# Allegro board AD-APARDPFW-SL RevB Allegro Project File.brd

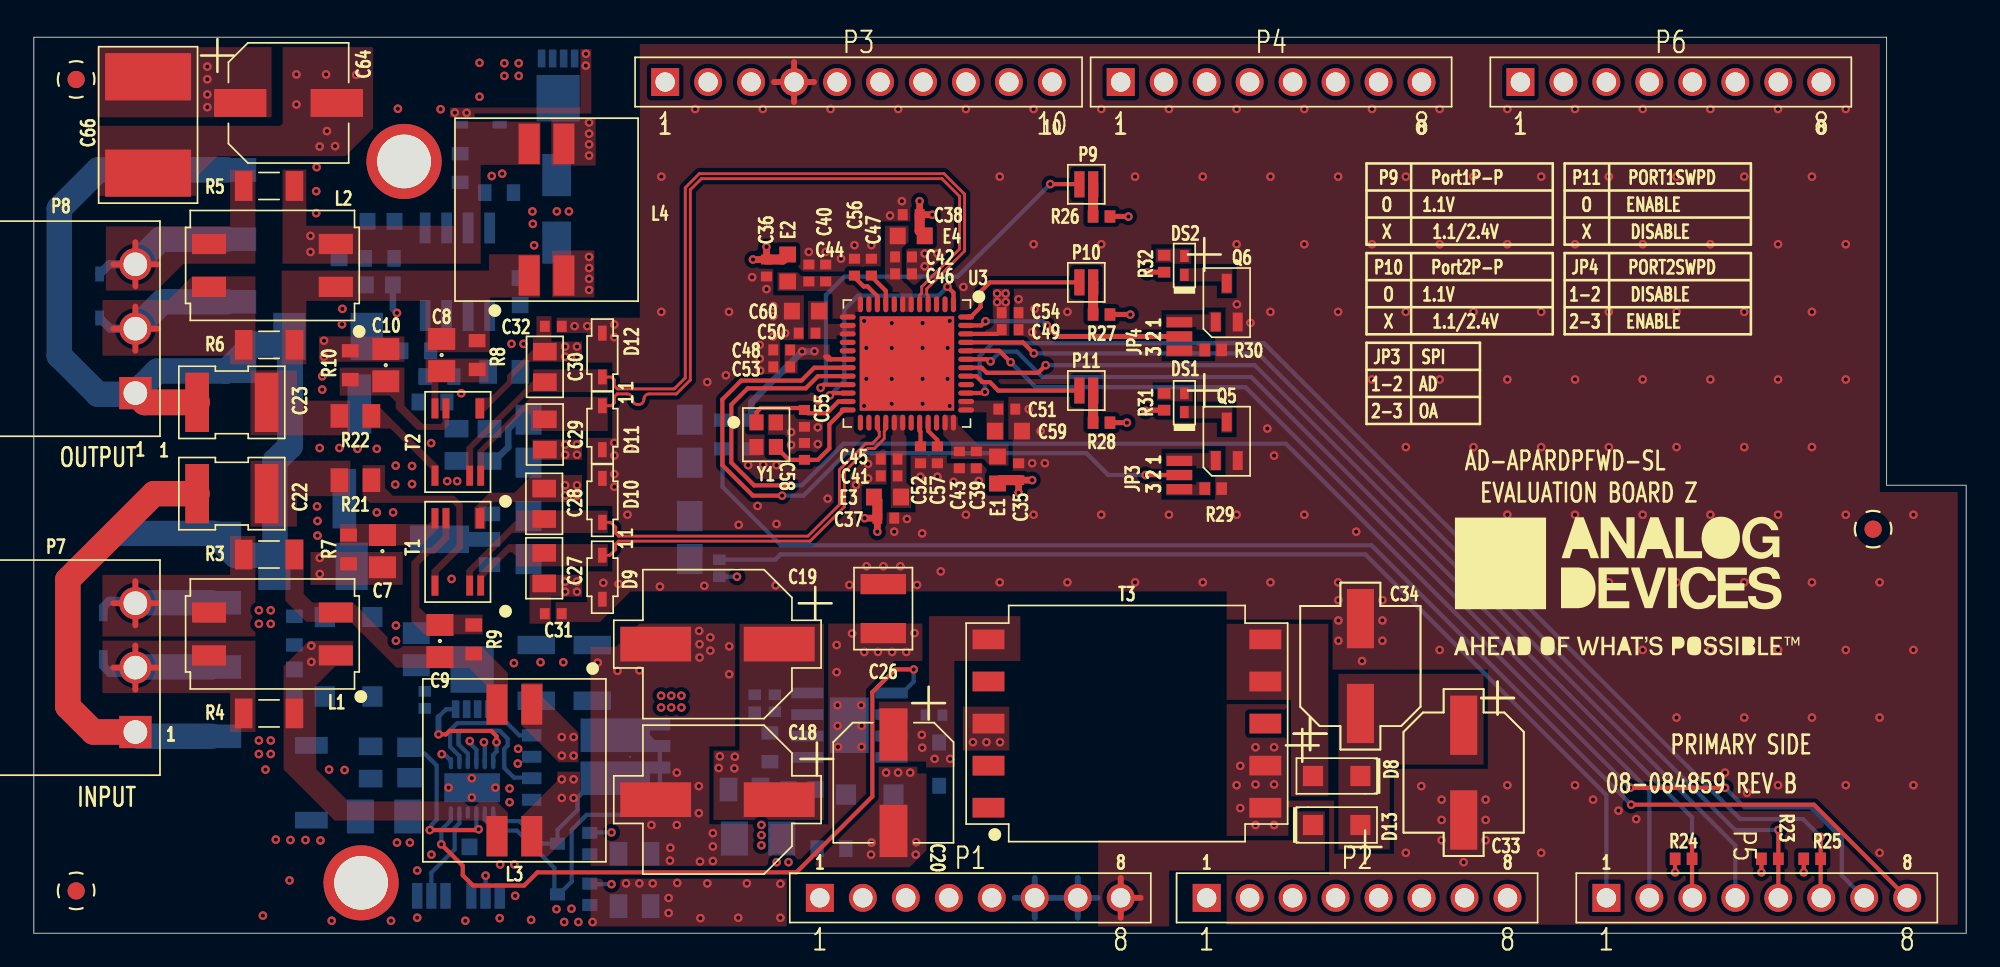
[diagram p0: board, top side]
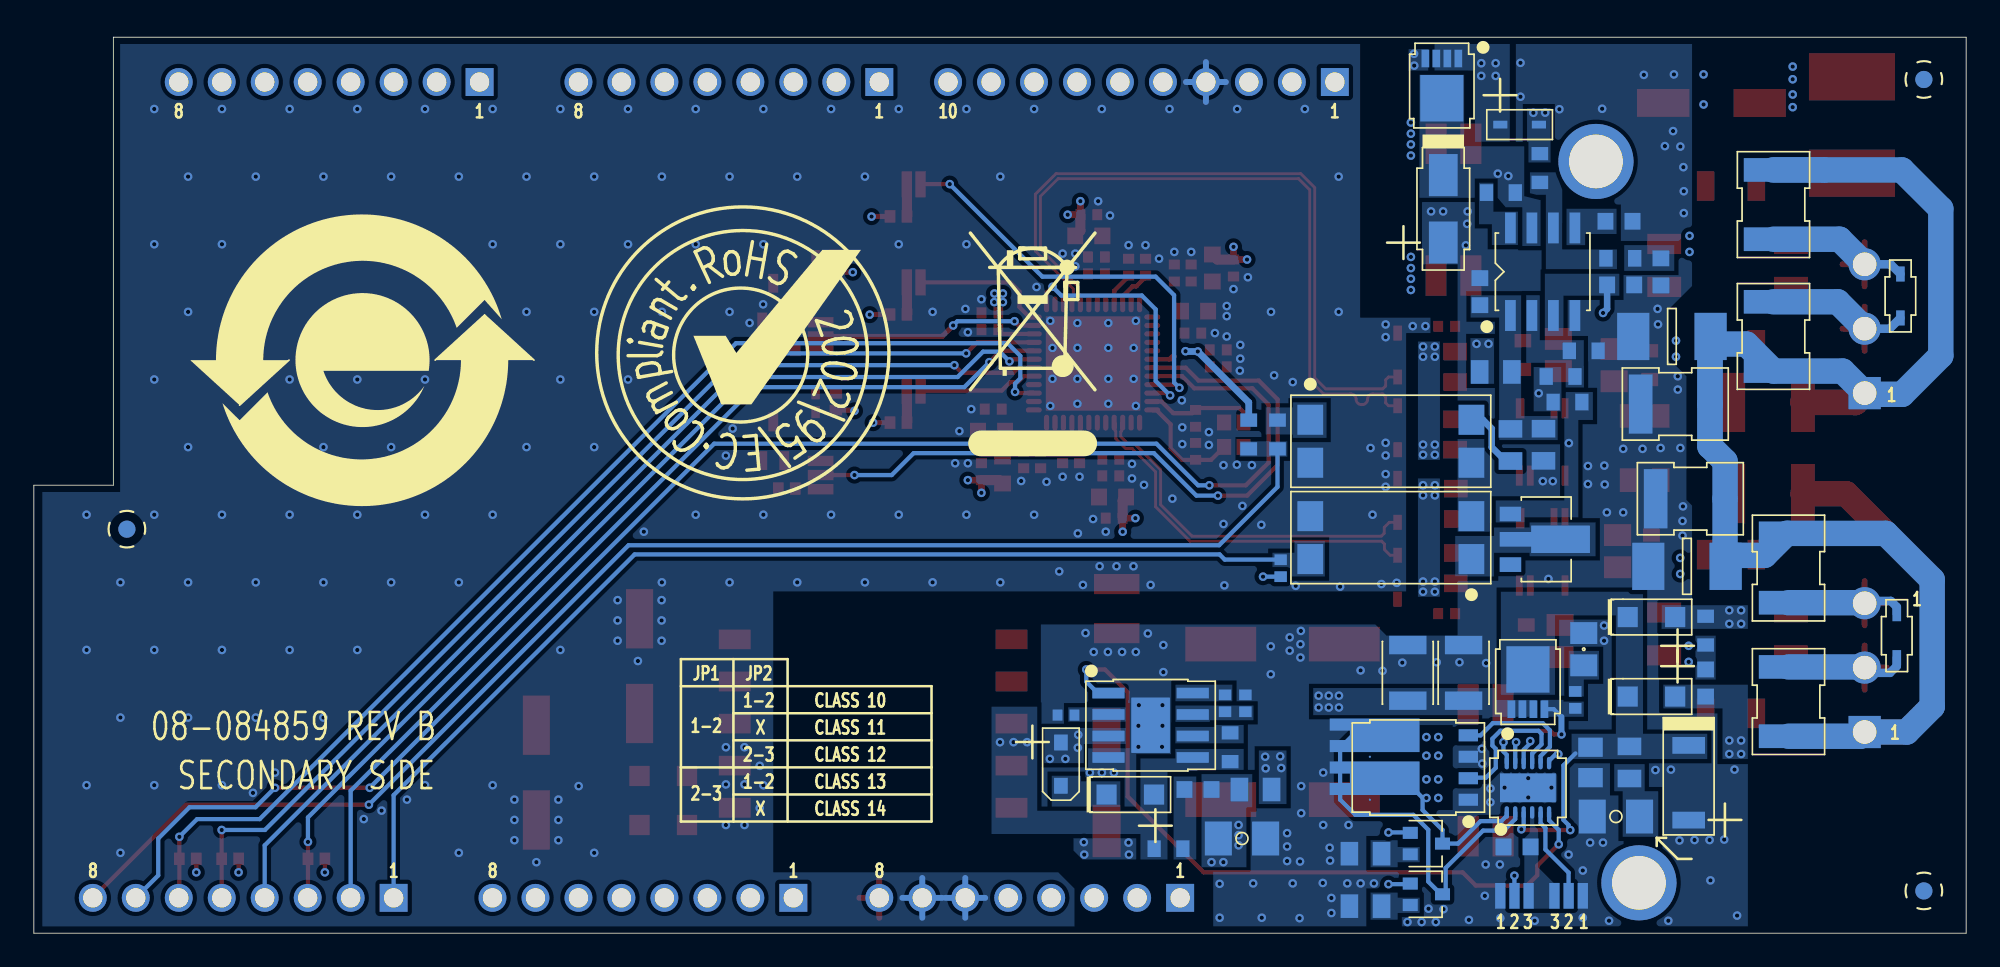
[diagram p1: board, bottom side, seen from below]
Outline 114.2 x 53 mm; copper layers: TOP, L2_PWR, L3_GND, BOTTOM. Coordinates in mm from the lower left corner of the outline.
Outline path: 0,53 109.5,53 109.5,26.5 114.2,26.5 114.2,0 0,0 0,53

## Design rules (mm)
constraint set DEFAULT: min track width 0.15
net group LTC_GATE: nets _N153 LTC_GATE
net group P2_TX: nets P2_TXN P2_TXP
net group 3V3_ARD: nets _N461 _N467 _N473 _N811 INT_N LT4256_UV_ISO SPI_CS SPI_MISO
net group LT4256_UV: nets _N154 _N710 _N711 _N712 _N767

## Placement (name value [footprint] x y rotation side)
C1  100pF  [C1812H71]  11.39 43.1 90 bottom
C2  100pF  [C1812H71]  10.5 21.6 90 bottom
C3  1000pF  [C1812H71]  16.3 25.7 0 bottom
C4  1000pF  [C1812H71]  17.19 31.3 0 bottom
C5  100pF  [C1812H71]  10.5 13.7 270 bottom
C6  100pF  [C1812H71]  11.39 35.3 270 bottom
C7  0.22uF  [C0805H60]  20.6 22.6 90 top
C8  0.22uF  [C0805H60]  24.1 34.2 270 top
C9  0.22uF  [C0805H60]  24 17.28 90 top
C10  0.22uF  [C0805H60]  20.8 33.6 270 top
C11  0.047UF  [C0603]  15.4 14.8 270 bottom
C12  150NF  [C1206H71]  20.7 6.9 0 bottom
C13  0.047uF  [C0805]  22.2 10.1 270 bottom
C14  0.022UF  [C0805H60]  22.6 16.8 270 bottom
C15  4.7uF  [C1210H87]  29.7 15.4 90 bottom
C16  4.7uF  [C1210H87]  33 15.4 90 bottom
C17  2.2uF  [C0603]  26.54 5.11 180 bottom
C18  33UF  [CPLSMSQ327H413]  40.4 7.9 180 top
C19  33UF  [CPLSMSQ327H413]  40.4 17.1 180 top
C20  22UF  [CPLSMSQ260H315]  50.8 8.9 270 top
C21  10UF  [C1206H71]  42.8 5.6 180 bottom
C22  100pF  [C1812H71]  11.7 26 0 top
C23  100pF  [C1812H71]  11.7 31.4 0 top
C24  1uF  [C0402]  53.2 12.9 0 bottom
C25  220pF  [C0603]  45.4 8.5 0 bottom
C26  4.7NF  [C1210H67]  50.2 19.2 90 top
C27  150pF  [C0805H30]  30.16 21.59 270 top
C28  150pF  [C0805H30]  30.16 25.4 270 top
C29  150pF  [C0805H30]  30.2 29.5 270 top
C30  150pF  [C0805H30]  30.2 33.5 270 top
C31  0.1uF  [C0402]  30.7 18.9 0 top
C32  0.1uF  [C0402]  30.7 35.9 0 top
C33  220UF  [CPLSMSQ260H303]  84.5 9.5 270 top
C34  220UF  [CPLSMSQ260H303]  78.4 15.8 90 top
C35  1uF  [C0402]  58.2 27.3 90 top
C36  1uF  [C0402]  43.3 39.35 270 top
C37  1uF  [C0402]  50.35 24.55 0 top
C38  1uF  [C0402]  51.85 42.5 180 top
C39  0.1uF  [C0402]  55.7 28 90 top
C40  0.1uF  [C0402]  45.8 39.05 90 top
C41  0.1uF  [C0402]  50.55 27.05 180 top
C42  0.1uF  [C0402]  51.4 40 0 top
C43  0.01uF  [C0402]  54.7 28 90 top
C44  0.01uF  [C0402]  46.8 39.05 90 top
C45  0.01uF  [C0402]  50.55 28.05 180 top
C46  0.01uF  [C0402]  51.4 39 0 top
C47  0.1uF  [C0402]  49.5 39.4 270 top
C48  0.01uF  [C0402]  44.2 34.5 180 top
C49  0.01uF  [C0402]  57.7 35.7 0 top
C50  0.1uF  [C0402]  45.7 35.5 180 top
C51  0.1uF  [C0402]  57.5 31 0 top
C52  0.1uF  [C0402]  52.4 28.3 270 top
C53  0.1uF  [C0402]  44.2 33.5 180 top
C54  0.1uF  [C0402]  57.7 36.7 0 top
C55  15pF  [C0402]  45.54 30.45 270 top
C56  1uF  [C0402]  48.5 39.4 90 top
C57  1uF  [C0402]  53.4 28.3 270 top
C58  15pF  [C0402]  45.54 28.5 90 top
C59  0.68UF  [C0603]  57.6 29.7 0 top
C60  0.68UF  [C0603]  45.6 36.8 180 top
C61  0.1UF  [C0603]  28.74 37.95 90 bottom
C62  1NF  [C0603]  18.04 39.12 270 bottom
C63  0.033uF  [C0603]  20.52 42.11 180 bottom
C64  22UF  [CPLSMSQ260H315]  15.05 49.11 0 top
C65  0.1UF  [C0603]  20.42 38.35 180 bottom
C66  22UF  [C2220H122]  6.75 47.81 270 top
D1  D55V0M1B2WSQ-7  [SOD323_B]  4.1 17.6 270 bottom
D2  D55V0M1B2WSQ-7  [SOD323_B]  3.89 37.69 270 bottom
D3  PMEG10020AELRX  [SOD123F]  18.6 18.7 180 bottom
D4  PMEG10020AELRX  [SOD123F]  18.6 14 180 bottom
D5  PTVS58VP1UTP  [SOD128]  16.4 8.9 270 bottom
D6  BZX384-B51  [SOD323-2]  53.5 10 90 bottom
D7  PMEG10020AELRX  [SOD123F]  49.4 8.2 180 bottom
D8  PMEG10020AELRX  [SOD123F]  77 9.3 180 top
D9  SP4020-01FTG  [SOD323_B]  33.6 21.06 270 top
D10  SP4020-01FTG  [SOD323_B]  33.6 25.6 90 top
D11  SP4020-01FTG  [SOD323_B]  33.6 29.9 270 top
D12  SP4020-01FTG  [SOD323_B]  33.6 34.2 90 top
D13  PMEG10020AELRX  [SOD123F]  77 6.4 0 top
D14  SMAT70A-13-F  [SMA-2]  30.9 42.85 270 bottom
D15  MM3Z11VB  [SOD323F]  26.39 47.83 0 bottom
DS1  APHHS1005CGCK  [LED0402_A]  68 31.38 90 top
DS2  APHHS1005CGCK  [LED0402_A]  68 39.5 90 top
E1  1KOHM AT 100MEGHZ  [L0603]  56.95 27.4 270 top
E2  1KOHM AT 100MEGHZ  [L0603]  44.55 39.35 270 top
E3  1KOHM AT 100MEGHZ  [L0603]  50.45 25.8 0 top
E4  1KOHM AT 100MEGHZ  [L0603]  51.85 41.25 180 top
JP1  3PIN_SOLDER_JUMPER  [JPRSLD03]  23.5 2.21 0 bottom
JP2  3PIN_SOLDER_JUMPER  [JPRSLD03]  26.7 2.21 180 bottom
JP3  3PIN_SOLDER_JUMPER  [JPRSLD03]  67.7 27.1 270 top
JP4  3PIN_SOLDER_JUMPER  [JPRSLD03]  67.7 35.3 270 top
L1  470UH  [LSML236W362H209]  14.1 17.7 90 top
L2  470UH  [LSML236W362H209]  14.1 39.5 90 top
L3  68UH  [LSMSQ406H197]  28.4 9.63 270 top
L4  68UH  [LSMSQ406H197]  30.3 42.8 90 top
NOREF  -  []  -272.1 -221.5 0 top
NOREF#2  -  [unnamed#2]  19.34 2.98 0 top
NOREF#3  -  []  109.5 53 180 top
NOREF#4  -  []  139.25 62 0 top
NOREF#5  -  []  0 0 0 top
NOREF#6  -  []  114.2 0 90 top
NOREF#7  -  [unnamed#2]  2.5 50.5 0 top
NOREF#8  -  []  -49.41 -241.98 0 top
NOREF#9  -  []  0 53 0 top
NOREF#10  -  []  -36 -105 0 top
NOREF#11  -  []  -36 -105 0 top
NOREF#12  -  [unnamed#2]  21.88 45.65 0 top
NOREF#13  -  []  -24.12 206.26 0 top
NOREF#14  -  []  93.58 20.51 0 top
NOREF#15  -  []  0 53 270 top
NOREF#16  -  [unnamed#2]  2.5 2.5 0 top
NOREF#17  -  []  7.6 -60.8 0 top
NOREF#18  -  []  55.75 67.75 0 top
NOREF#19  -  [unnamed#2]  108.7 23.9 0 top
NOREF#20  -  []  114.2 0 90 top
NOREF#21  -  [unnamed#2]  108.7 23.9 180 bottom
NOREF#22  -  []  94.8 33.9 180 bottom
NOREF#23  -  []  72.3 34.2 180 bottom
NOREF#24  -  [unnamed#2]  2.5 50.5 180 bottom
NOREF#25  -  [unnamed#2]  2.5 2.5 180 bottom
NOREF#26  -  []  45.9 45.1 180 bottom
P1  ESQ-108-24-T-S  [CNTHFHDR1X8L820W95H545]  46.45 2.09 0 top
P2  ESQ-108-24-T-S  [CNTHFHDR1X8L820W95H545]  69.31 2.09 0 top
P3  ESQ-110-24-T-S  [CNTHFHDR1X10L1020W95H545]  37.31 50.35 0 top
P4  ESQ-108-24-T-S  [CNTHFHDR1X8L820W95H545]  64.23 50.35 0 top
P5  ESQ-108-24-T-S  [CNTHFHDR1X8L820W95H545]  92.94 2.09 0 top
P6  ESQ-108-24-T-S  [CNTHFHDR1X8L820W95H545]  87.86 50.35 0 top
P7  TBP02R1-381-03BE  [CNCUITBP02R1-381-03BE]  6 11.9 90 top
P8  TBP02R1-381-03BE  [CNCUITBP02R1-381-03BE]  6 31.95 90 top
P9  -  [JPSLD02]  62.2 44.3 0 top
P10  -  [JPSLD02]  62.2 38.5 0 top
P11  -  [JPSLD02]  62.2 32.1 0 top
Q1  BSS123WQ-7-F  [SOT323]  31.9 5.3 270 bottom
Q2  BSS123WQ-7-F  [SOT323]  31.9 2.3 270 bottom
Q3  BUK9K29-100E,115  [SOT1205]  32.7 9.8 90 bottom
Q4  PSMN075-100MSEX  [SOT1210]  25.9 14.9 180 bottom
Q5  BSS138PW,115  [SC-70-3]  70.5 29.1 0 top
Q6  BSS138PW,115  [SC-70-3]  70.5 37.3 0 top
Q7  PSMN075-100MSEX  [SOT1210]  30.99 50.09 0 bottom
Q8  FOD817AS  [SMD4]  34 23.4 90 bottom
Q9  FOD817AS  [SMD4]  34 29.1 270 bottom
R1  4.7MEG  [R2010]  16.5 21.7 0 bottom
R2  4.7MEG  [R2010]  17.39 35.3 0 bottom
R3  10K  [R1206]  13.9 22.4 0 top
R4  10K  [R1206]  13.9 13 0 top
R5  10K  [R1206]  13.9 44.2 0 top
R6  10K  [R1206]  13.9 34.8 0 top
R7  1MEG  [R0603]  18.6 22.7 90 top
R8  1MEG  [R0603]  26.2 34.2 270 top
R9  1MEG  [R0603]  26 17.38 90 top
R10  1MEG  [R0603]  18.7 33.6 270 top
R11  3.3  [R0805]  35.5 4.7 0 bottom
R12  100  [R0603]  15.4 17.9 270 bottom
R13  3.3  [R0805]  35.5 1.6 0 bottom
R14  40.2  [R0805]  19.9 10.1 270 bottom
R15  10K  [R0402]  23.1 13.8 270 bottom
R16  3.3  [R0805]  42 8.5 180 bottom
R17  10K  [R0402]  42.6 13.6 90 bottom
R18  100K  [R0402]  43.8 13.6 90 bottom
R19  261K  [R0603]  43.5 11 270 bottom
R20  100  [R0603]  47.14 5 0 bottom
R21  100  [R0805]  19 26.8 0 top
R22  100  [R0805]  19 30.6 0 top
R23  100K  [R0402]  102.6 4.4 0 top
R24  100K  [R0402]  97.5 4.4 0 top
R25  1.5K  [R0402]  105.1 4.4 0 top
R26  4.7K  [R0402]  63.1 42.4 0 top
R27  4.7K  [R0402]  63.1 36.6 0 top
R28  4.7K  [R0402]  63.1 30.2 0 top
R29  4.7K  [R0402]  69.7 26.3 0 top
R30  4.7K  [R0402]  69.7 34.5 0 top
R31  1K  [R0402]  66.8 31.44 90 top
R32  1K  [R0402]  66.8 39.6 90 top
R33  0.075  [R0603]  27.5 43.81 0 bottom
R34  100  [R0603]  20.44 39.92 180 bottom
R35  10  [R0603]  25.2 45.26 270 bottom
R36  100K  [R0603]  23.97 32.93 180 bottom
R37  24.3K  [R0603]  22.6 34.45 0 bottom
R39  34K  [R0603]  23.56 31.42 180 bottom
R40  10K  [R0402]  40.51 21.59 90 bottom
R41  100  [R0603]  40.7 29.5 90 bottom
R42  330K  [R0805]  27.8 33.2 180 bottom
R43  20K  [R0805]  26.93 28.88 270 bottom
R44  10K  [R0603]  42.4 29.5 270 bottom
R45  330K  [R0805]  24.98 28.89 270 bottom
T1  74930000  [TSML185W127H114_A]  25.06 22.56 90 top
T2  74930000  [TSML185W127H114_A]  25.06 29.06 90 top
T3  750315126  [TSMSQ530H505]  64.6 12.4 90 top
U1  LTC9111RDE#PBF  [DFN12_4X3_PAD3_3X1_7-05-08-1695]  25.9 8.6 180 bottom
U2  LT8304IS8E#PBF  [SO8NB_PAD3_27X2_28-05-08-1857]  48.2 12.3 270 bottom
U3  ADIN2111CCPZ  [QFN48_7X7_PAD5_6X5_6]  51.6 33.7 180 top
U4  LT4256-2IS8#TRPBF  [SO8NB-5]  25.03 39.13 180 bottom
U5  CL2N8-G  [SOT-89-2]  24.9 23.3 270 bottom
Y1  25MEGHZ  [YSML79W63H20]  43.28 29.49 270 top

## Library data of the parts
C1 C2 C5 C6 C22 C23 = CAP: Tolerance: 5; User Part Number: UPN; alternate symbols: (C1812H71); tolerance: 5
C3 C4 = CAP: Tolerance: 10; User Part Number: UPN; alternate symbols: (C1812H71); tolerance: 10
C7-C10 C14 = CAP: Tolerance: 5; User Part Number: UPN; alternate symbols: (C0805H60); tolerance: 5
C11 C17 C59-C62 C65 = CAP: User Part Number: UPN; Tolerance: 10; alternate symbols: (C0603); tolerance: 10
C12 C21 = CAP: Tolerance: 10; User Part Number: UPN; alternate symbols: (C1206H71); tolerance: 10
C13 = CAP: User Part Number: UPN; Tolerance: 10; alternate symbols: (C0805); tolerance: 10
C15 C16 = CAP: Tolerance: 10; User Part Number: UPN; alternate symbols: (C1210H87); tolerance: 10
C18 C19 = CAPP: User Part Number: UPN; Tolerance: 20; alternate symbols: (CPLSMSQ327H413); tolerance: 20
C20 C64 = CAPP: Tolerance: 20; User Part Number: UPN; alternate symbols: (CPLSMSQ260H315); tolerance: 20
C24 C31 C32 C35-C54 C56 C57 = CAP: User Part Number: UPN; Tolerance: 10; alternate symbols: (C0402); tolerance: 10
C25 C63 = CAP: User Part Number: UPN; Tolerance: 5; alternate symbols: (C0603); tolerance: 5
C26 = CAP: Tolerance: 10; User Part Number: UPN; alternate symbols: (C1210H67); tolerance: 10
C27-C30 = CAP: Tolerance: 1; User Part Number: UPN; alternate symbols: (C0805H30); tolerance: 1
C33 C34 = CAPP: User Part Number: UPN; Tolerance: 20; alternate symbols: (CPLSMSQ260H303); tolerance: 20
C55 C58 = CAP: User Part Number: UPN; Tolerance: 1; alternate symbols: (C0402); tolerance: 1
C66 = CAP: Tolerance: 20; User Part Number: UPN; alternate symbols: (C2220H122); tolerance: 20
D1 D2 = DIOZNR_V2: Tolerance: N/A; User Part Number: UPN; alternate symbols: (SOD323_B); tolerance: N/A
D3 D4 D7 D8 D13 = DIOSCHOTTKY: Tolerance: N/A; User Part Number: UPN; alternate symbols: (SOD123F); tolerance: N/A
D5 = DIOZNR: User Part Number: UPN; Tolerance: N/A; alternate symbols: (SOD128); tolerance: N/A
D6 = DIOZNR: Tolerance: 2; User Part Number: UPN; alternate symbols: (SOD323-2); tolerance: 2
D9-D12 = DIOZNR_V4: Tolerance: N/A; User Part Number: UPN; alternate symbols: (SOD323_B); tolerance: N/A
D14 = DIOTVS: User Part Number: UPN; Tolerance: N/A; alternate symbols: (SMA-2); tolerance: N/A
D15 = DIOZNR: Tolerance: 2; User Part Number: UPN; alternate symbols: (SOD323F); tolerance: 2
DS1 DS2 = DIOLED: User Part Number: UPN; Tolerance: N/A; alternate symbols: (LED0402_A); tolerance: N/A
E1-E4 = FERRITE: User Part Number: UPN; Tolerance: 25; alternate symbols: (L0603); tolerance: 25
JP1-JP4 = NC3P_JMPR: Tolerance: N/A; User Part Number: UPN; alternate symbols: (JPRSLD03); tolerance: N/A
L1 L2 = CHOKE4P_V5: User Part Number: UPN; Tolerance: 50; alternate symbols: (LSML236W362H209); tolerance: 50
L3 L4 = IND_4P_V4: User Part Number: UPN; Tolerance: 20; alternate symbols: (LSMSQ406H197); tolerance: 20
P1 P2 P4-P6 = CN8P_A: User Part Number: UPN; Tolerance: N/A; alternate symbols: (CNTHFHDR1X8L820W95H545); tolerance: N/A
P3 = CN10P: User Part Number: UPN; Tolerance: N/A; alternate symbols: (CNTHFHDR1X10L1020W95H545); tolerance: N/A
P7 P8 = CN3P: User Part Number: UPN; Tolerance: N/A; alternate symbols: (CNCUITBP02R1-381-03BE); tolerance: N/A
P9-P11 = NC2P: User Part Number: UPN; Tolerance: N/A; alternate symbols: (JPSLD02); tolerance: N/A
Q1 Q2 = TRANNMOSFET_V8: User Part Number: UPN; Tolerance: N/A; alternate symbols: (SOT323); tolerance: N/A
Q3 = TRANNMOSFET_DUAL: Tolerance: N/A; User Part Number: UPN; alternate symbols: (SOT1205); tolerance: N/A
Q4 Q7 = TRANNMOSFET_V15: Tolerance: N/A; User Part Number: UPN; alternate symbols: (SOT1210); tolerance: N/A
Q5 Q6 = TRANNMOSFET_V8: Tolerance: N/A; User Part Number: UPN; alternate symbols: (SC-70-3); tolerance: N/A
Q8 Q9 = TRANOPTO: Tolerance: N/A; User Part Number: UPN; alternate symbols: (SMD4); tolerance: N/A
R1 R2 = RES: Tolerance: 5; User Part Number: UPN; alternate symbols: (R2010); tolerance: 5
R3-R6 = RES: User Part Number: UPN; Tolerance: 1; alternate symbols: (R1206); tolerance: 1
R7-R10 R12 R19 R20 R33 R34 R36 R37 R39 R41 R44 = RES: User Part Number: UPN; Tolerance: 1; alternate symbols: (R0603); tolerance: 1
R11 R13 R16 R42 R45 = RES: User Part Number: UPN; Tolerance: 5; alternate symbols: (R0805); tolerance: 5
R14 R21 R22 R43 = RES: User Part Number: UPN; Tolerance: 1; alternate symbols: (R0805); tolerance: 1
R15 R17 R23-R25 R31 R32 R40 = RES: User Part Number: UPN; Tolerance: 1; alternate symbols: (R0402); tolerance: 1
R18 R26-R30 = RES: User Part Number: UPN; Tolerance: 5; alternate symbols: (R0402); tolerance: 5
R35 = RES: User Part Number: UPN; Tolerance: 0.5; alternate symbols: (R0603); tolerance: 0.5
T1 T2 = XFMR7P_V2: User Part Number: UPN; Tolerance: N/A; alternate symbols: (TSML185W127H114_A); tolerance: N/A
T3 = XFMR10P_V16: User Part Number: UPN; Tolerance: N/A; alternate symbols: (TSMSQ530H505); tolerance: N/A
U1 = ADLTC9111_V2: User Part Number: UPN; Tolerance: N/A; alternate symbols: (DFN12_4X3_PAD3_3X1_7-05-08-1695); tolerance: N/A
U2 = ADLT8304: Tolerance: N/A; User Part Number: UPN; alternate symbols: (SO8NB_PAD3_27X2_28-05-08-1857); tolerance: N/A
U3 = ADIN2111: User Part Number: UPN; Tolerance: N/A; alternate symbols: (QFN48_7X7_PAD5_6X5_6); tolerance: N/A
U4 = ADLT4256_X: Tolerance: N/A; User Part Number: UPN; alternate symbols: (SO8NB-5); tolerance: N/A
U5 = ICCL2: User Part Number: UPN; Tolerance: N/A; alternate symbols: (SOT-89-2); tolerance: N/A
Y1 = XTAL4PIN_V3: Tolerance: 10PPM; User Part Number: UPN; alternate symbols: (YSML79W63H20); tolerance: 10PPM

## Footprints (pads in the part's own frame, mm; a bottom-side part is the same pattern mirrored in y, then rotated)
C0402
  rect 0.584x0.66 smd: 1(-0.5,0) 2(0.5,0)
C0603
  rect 0.94x0.991 smd: 1(-0.8,0) 2(0.8,0)
C0805
  rect 1.143x1.448 smd: 1(-0.9,0) 2(0.9,0)
C0805H30
  rect 1.041x1.397 smd: 1(-0.9,0) 2(0.9,0)
C0805H60
  rect 1.295x1.6 smd: 1(-0.952,0) 2(0.952,0)
C1206H71
  rect 1.6x2.007 smd: 1(-1.397,0) 2(1.397,0)
C1210H67
  rect 1.194x2.692 smd: 1(-1.448,0) 2(1.448,0)
C1210H87
  rect 1.092x2.21 smd: 1(-1.646,0) 2(1.646,0)
C1812H71
  rect 1.397x3.505 smd: 1(-2.05,0) 2(2.05,0)
C2220H122
  rect 2.794x5.08 smd: 1(-2.85,0) 2(2.85,0)
CNCUITBP02R1-381-03BE
  rect 1.905x1.905 hole 1.397: 1(0,0)
  round 1.905 hole 1.397: 2(3.81,0) 3(7.62,0)
CNTHFHDR1X8L820W95H545
  rect 1.651x1.651 hole 1.143: 1(0,0)
  round 1.651 hole 1.143: 2(2.54,0) 3(5.08,0) 4(7.62,0) 5(10.16,0) 6(12.7,0) 7(15.24,0) 8(17.78,0)
CNTHFHDR1X10L1020W95H545
  rect 1.651x1.651 hole 1.143: 1(0,0)
  round 1.651 hole 1.143: 2(2.54,0) 3(5.08,0) 4(7.62,0) 5(10.16,0) 6(12.7,0) 7(15.24,0) 8(17.78,0) 9(20.32,0) 10(22.86,0)
CPLSMSQ260H303
  rect 3.505x1.6 smd: N(2.803,0) P(-2.803,0)
CPLSMSQ260H315
  rect 3.099x1.651 smd: N(2.85,0) P(-2.85,0)
CPLSMSQ327H413
  rect 4.191x2.057 smd: N(3.65,0) P(-3.65,0)
DFN12_4X3_PAD3_3X1_7-05-08-1695
  oval 0.254x0.737 smd: 1(-1.25,-1.46) 2(-0.75,-1.46) 3(-0.25,-1.46) 4(0.25,-1.46) 5(0.75,-1.46) 6(1.25,-1.46) 7(1.25,1.46) 8(0.75,1.46) 9(0.25,1.46) 10(-0.25,1.46) 11(-0.75,1.46) 12(-1.25,1.46)
  rect 3.302x1.702 smd: 13(0,0)
JPRSLD03
  rect 0.61x1.524 smd: 1(-0.838,0) 2(0,0) 3(0.838,0)
JPSLD02
  rect 0.61x1.549 smd: 1(-0.406,0) 2(0.406,0)
L0603
  rect 0.94x0.991 smd: 1(-0.8,0) 2(0.8,0)
LED0402_A
  rect 0.711x0.508 smd: A(0.556,0) C(-0.556,0)
LSML236W362H209
  rect 1.194x2.007 smd: 1(-1.27,-3.747) 2(1.27,-3.747) 3(1.27,3.747) 4(-1.27,3.747)
LSMSQ406H197
  rect 2.388x1.245 smd: 1(-3.899,1.029) 2(-3.899,-1.029) 3(3.899,-1.029) 4(3.899,1.029)
QFN48_7X7_PAD5_6X5_6
  oval 0.305x0.94 smd: 1(-2.75,-3.5) 2(-2.25,-3.5) 3(-1.75,-3.5) 4(-1.25,-3.5) 5(-0.75,-3.5) 6(-0.25,-3.5) 7(0.25,-3.5) 8(0.75,-3.5) 9(1.25,-3.5) 10(1.75,-3.5) 11(2.25,-3.5) 12(2.75,-3.5) 25(2.75,3.5) 26(2.25,3.5) 27(1.75,3.5) 28(1.25,3.5) 29(0.75,3.5) 30(0.25,3.5) 31(-0.25,3.5) 32(-0.75,3.5) 33(-1.25,3.5) 34(-1.75,3.5) 35(-2.25,3.5) 36(-2.75,3.5)
  oval 0.94x0.305 smd: 13(3.5,-2.75) 14(3.5,-2.25) 15(3.5,-1.75) 16(3.5,-1.25) 17(3.5,-0.75) 18(3.5,-0.25) 19(3.5,0.25) 20(3.5,0.75) 21(3.5,1.25) 22(3.5,1.75) 23(3.5,2.25) 24(3.5,2.75) 37(-3.5,2.75) 38(-3.5,2.25) 39(-3.5,1.75) 40(-3.5,1.25) 41(-3.5,0.75) 42(-3.5,0.25) 43(-3.5,-0.25) 44(-3.5,-0.75) 45(-3.5,-1.25) 46(-3.5,-1.75) 47(-3.5,-2.25) 48(-3.5,-2.75)
  rect 5.588x5.588 smd: PAD(0,0)
R0402
  rect 0.635x0.737 smd: 1(-0.5,0) 2(0.5,0)
R0603
  rect 0.787x0.991 smd: 1(-0.85,0) 2(0.85,0)
R0805
  rect 1.041x1.397 smd: 1(-0.95,0) 2(0.95,0)
R1206
  rect 1.041x1.753 smd: 1(-1.5,0) 2(1.5,0)
R2010
  rect 1.905x2.794 smd: 1(-2.286,0) 2(2.286,0)
SC-70-3
  rect 0.584x1.118 smd: 1(-0.65,-1.144) 2(0.65,-1.144) 3(0,1.144)
SMA-2
  rect 2.489x1.702 smd: A(1.995,0) C(-1.995,0)
SMD4
  rect 1.778x1.524 smd: 1(-1.27,-4.763) 2(1.27,-4.763) 3(1.27,4.763) 4(-1.27,4.763)
SO8NB-5
  rect 0.635x1.829 smd: 1(-1.905,-2.591) 2(-0.635,-2.591) 3(0.635,-2.591) 4(1.905,-2.591) 5(1.905,2.591) 6(0.635,2.591) 7(-0.635,2.591) 8(-1.905,2.591)
SO8NB_PAD3_27X2_28-05-08-1857
  rect 0.635x1.905 smd: 1(-1.905,-2.49) 2(-0.635,-2.49) 3(0.635,-2.49) 4(1.905,-2.49) 5(1.905,2.49) 6(0.635,2.49) 7(-0.635,2.49) 8(-1.905,2.49)
  rect 3.277x2.286 smd: 9(0,0)
SOD123F
  rect 1.194x1.194 smd: A(1.403,0) C(-1.403,0)
SOD128
  rect 0.991x1.93 smd: A(2.21,0) C(-2.21,0)
SOD323-2
  rect 0.94x0.813 smd: A(1.28,0) C(-1.28,0)
SOD323_B
  rect 0.889x0.508 smd: 1(-1.3,0) 2(1.3,0)
SOD323F
  rect 0.838x0.457 smd: A(1.14,0) C(-1.14,0)
SOT323
  rect 0.711x0.889 smd: 1(-0.635,-0.952) 2(0.635,-0.952) 3(0,0.952)
SOT1205
  rect 0.711x1.143 smd: 1(-1.905,-3.278) 2(-0.635,-3.278) 3(0.635,-3.278) 4(1.905,-3.278)
  custom 0.495x0.495 smd: 5(1.905,2.26) 7(-0.635,2.26)
  round 0.127 smd: 6(0.635,2.54) 8(-1.905,2.54)
SOT1210
  rect 0.457x1.041 smd: 1(-0.975,-1.65) 2(-0.325,-1.65) 3(0.325,-1.65) 4(0.975,-1.65)
  round 0.127 smd: 5(0.975,1.65) 6(0.325,1.65) 7(-0.325,1.65) 8(-0.975,1.65)
SOT-89-2
  rect 0.864x1.27 smd: 1(-1.499,-2.032) 3(1.499,-2.032)
  custom 0.406x0.406 smd: 2(0,0)
TSML185W127H114_A
  rect 1.194x0.406 smd: 1(-1.99,-1.35) 2(-1.99,-0.7) 3(-1.99,1.35) 6(1.99,0.7) 7(1.99,1.35)
  round 0.127 smd: 4(-1.69,1.35)
  rect 1.194x0.508 smd: 5(1.99,-1.305)
TSMSQ530H505
  rect 1.168x1.88 smd: 1(-4.978,8.179) 2(-2.489,8.179) 3(0,8.179) 4(2.489,8.179) 5(4.978,8.179) 6(4.978,-8.179) 7(2.489,-8.179) 8(0,-8.179) 9(-2.489,-8.179) 10(-4.978,-8.179)
unnamed#2
  round 4.445 hole 3.175 unplated: (0,0)
YSML79W63H20
  rect 0.94x0.838 smd: 1(-0.725,-0.575) 2(0.725,-0.575) 3(0.725,0.575) 4(-0.725,0.575)

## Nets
3V3_ARD: C35.1 C36.1 C37.1 C38.1 C48.1 C49.1 C53.1 C54.1 E1.2(N2) E2.1 E3.1 E4.1 P1.4 R23.1 R24.1 R25.1 R26.2(N2) R27.2(N2) R28.2(N2) R31.1 R32.1 R40.1 R44.1 U3.18 U3.46
12V_ISO: D13.C P1.8(N8)
DGND: C26.2(N2) C31.2(N2) C32.2(N2) C33.N(N2) C34.N(N2) C35.2(N2) C36.2(N2) C37.2(N2) C38.2(N2) C39.1 C40.2(N2) C41.2(N2) C42.2(N2) C43.1 C44.2(N2) C45.2(N2) C46.2(N2) C47.1 C48.2(N2) C49.2(N2) C50.2(N2) C51.2(N2) C52.2(N2) C53.2(N2) C54.2(N2) C55.2(N2) C56.2(N2) C57.2(N2) C58.2(N2) C59.2(N2) C60.2(N2) D9.2(N2) D10.2(N2) D11.2(N2) D12.2(N2) P1.6 P1.7 P3.4 Q5.2(S) Q6.2(S) Q8.3(E) Q9.2 R29.2(N2) R30.2(N2) T3.9 T3.10 U3.PAD Y1.2 Y1.4
GND: C3.2(N2) C4.2(N2) C12.2(N2) C13.2(N2) C14.1 C15.2(N2) C16.2(N2) C17.1 C18.N(N2) C19.N(N2) C20.N(N2) C21.2(N2) C24.2(N2) C26.1 C61.2(N2) C62.2(N2) C63.2(N2) C64.N(N2) C65.2(N2) C66.2(N2) D5.A(P) D14.A(P) JP1.1 JP2.1 L4.3 Q3.1 Q3.3(S) Q8.2 Q9.3(E) R1.2(N2) R2.2(N2) R11.2(N2) R13.2(N2) R17.2(N2) R37.1 R45.2(N2) U1.13 U2.4 U2.9 U4.4
GND_EARTH: C1.2(N2) C2.2(N2) C3.1 C4.1 C5.2(N2) C6.2(N2) C22.1 C23.1 P7.1 P8.1 R1.1 R2.1
_N149: C5.1 D1.2(N2) L1.4(N4) P7.2 R4.1
_N150: C2.1 D1.1 L1.3 P7.3(N3) R3.1
_N151: C11.1 R12.2(N2)
_N152: C12.1 R14.2(N2)
_N153: C14.2(N2) R15.1
_N154: C18.P C19.P R16.2(N2)
_N155: Q1.2(S) R11.1
_N156: Q2.2(S) R13.1
_N157: JP1.2(COM) U1.5
_N158: JP2.2(COM) U1.10
_N217: C6.1 D2.2(N2) L2.4(N4) P8.2 R6.1
_N218: C1.1 D2.1 L2.3 P8.3(N3) R5.1
_N234: C13.1 D3.C D4.C D5.C Q4.5 Q4.6 Q4.7 Q4.8 R14.1 U1.3
_N431: JP3.3 R29.1
_N432: JP3.1 Q5.1
_N433: DS1.C Q5.3
_N434: DS1.A(P) R31.2(N2)
_N448: JP4.3 R30.1
_N449: JP4.1 Q6.1
_N450: DS2.C Q6.3
_N451: DS2.A(P) R32.2(N2)
_N460: P9.1 U3.21
_N461: P9.2(N2) R26.1
_N467: P10.2(N2) R27.1
_N473: P11.2(N2) R28.1
_N477: P10.1 U3.48
_N478: P11.1 U3.41
_N489: C22.2(N2) R21.1
_N490: R21.2(N2) T1.3 T1.4
_N491: C27.2(N2) C28.1 C31.1 T1.5
_N514: C23.2(N2) R22.1
_N515: R22.2(N2) T2.3 T2.4
_N516: C29.2(N2) C30.1 C32.1 T2.5
_N676: C42.1 C46.1 E4.2(N2) U3.6 U3.7
_N682: C41.1 C45.1 E3.2(N2) U3.29 U3.30
_N687: C40.1 C44.1 E2.2(N2) U3.12 U3.13
_N694: C39.2(N2) C43.2(N2) E1.1 U3.35 U3.36
_N709: D6.C D7.C
_N710: C25.2(N2) R20.1
_N711: R19.1 U2.6
_N712: D7.A(P) R19.2(N2) R20.2(N2) T3.3 U2.5
_N713: C24.1 U2.2
_N716: R17.1 R18.1 U2.7
_N721: C33.P C34.P D8.C D13.A(P)
_N735: D8.A(P) T3.6 T3.7
_N738: C63.1 U4.5
_N744: R34.1 R35.2(N2) U4.6
_N749: R36.2(N2) R37.2(N2) U4.2
_N756: Q8.1 U5.2(VB)
_N767: Q9.4 R43.2(N2)
_N810: C62.1 R34.2(N2)
_N811: Q9.1 R41.2(N2)
_N814: R33.2(N2) U4.8(VCC)
CEXT_2: C47.2(N2) U3.9
CEXT_3: C56.1 U3.10
CEXT_6: C52.1 U3.32
CEXT_7: C57.1 U3.33
CLK_REF: U3.1 U3.22
DATA_N1: C7.2(N2) R7.2(N2) T1.7(SEC_2)
DATA_N2: C8.2(N2) R8.2(N2) T2.7(SEC_2)
DATA_P1: C9.2(N2) R9.2(N2) T1.6
DATA_P2: C10.2(N2) R10.2(N2) T2.6
DLDO1_1P1: C51.1 C59.1 U3.37 U3.38
DLDO2_1P1: C50.1 C60.1 U3.14 U3.15
INT_N: P5.6 R25.2(N2) U3.39
LGATE1: Q3.2 U1.9
LGATE2: Q3.4 U1.8
LT4256_GATE: D15.C Q7.4 R35.1
LT4256_OUT: C64.P C66.1 D15.A(P) L4.2 Q7.1 Q7.2 Q7.3(S3) R36.1 R39.1
LT4256_PWRGD: C65.1 R39.2(N2) U4.3 U5.1
LT4256_UV: C61.1 R42.2(N2) R43.1 R45.1 U4.1
LT4256_UV_ISO: P5.8(N8) R41.1 R44.2(N2)
LT8304_EN: U1.6 U2.1
LTC_GATE: Q4.4 R15.2(N2) U1.12
LTC_OUT: C15.1 C16.1 C20.P C21.1 C25.1 D6.A(P) D14.C Q4.1 Q4.2 Q4.3(S3) Q7.5 Q7.6 Q7.7 Q7.8 R16.1 R33.1 R42.1 T3.5 U1.11 U2.3(VIN) U4.7
P1_LED_0/SPI_CFG1: JP3.2(COM) U3.19
P1_TXN: C28.2(N2) D10.1 T1.2 U3.27
P1_TXP: C27.1 D9.1 T1.1 U3.28
P2_LED_0/P2_SWPD_EN_N: JP4.2(COM) U3.47
P2_TXN: C30.2(N2) D12.1 T2.2 U3.4
P2_TXP: C29.1 D11.1 T2.1 U3.5
POWER_AND_DATA_N1: C7.1 L1.1 L3.3 R4.2(N2) R7.1
POWER_AND_DATA_N2: C8.1 L2.1 L4.1 R6.2(N2) R8.1
POWER_AND_DATA_P1: C9.1 L1.2 L3.2 R3.2(N2) R9.1
POWER_AND_DATA_P2: C10.1 L2.2 L4.4(N4) R5.2(N2) R10.1
POWER_N: C11.2(N2) D4.A(P) L3.1 Q2.3 Q3.5 Q3.6 U1.2
POWER_P: D3.A(P) L3.4(N4) Q1.3 Q3.7 Q3.8 R12.1 U1.1
PWRGD_ISO: P5.1 Q8.4 R40.2(N2)
RESET_N: P5.7 U3.20
SCCP: Q1.1 Q2.1 U1.7
SPI_CS: P5.5 R23.2(N2) U3.45
SPI_MISO: P5.3 R24.2(N2) U3.43
SPI_MOSI: P5.4 U3.42
SPI_SCK: P5.2 U3.44
STBY: C17.2(N2) JP1.3 JP2.3 U1.4(STBY)
TC: R18.2(N2) U2.8
XTAL_I: C55.1 U3.23 Y1.1
XTAL_O: C58.1 U3.24(XTAL_O) Y1.3(N2)

Pads without a net: P1 1 2 3 5; P2 1 2 3 4 5 6 7 8; P3 1 2 3 5 6 7 8 9 10; P4 1 2 3 4 5 6 7 8; P6 1 2 3 4 5 6 7 8; T3 1 2 4 8; U3 2 3 8 11 16 17 25 26 31 34 40; U5 3

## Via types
v1: diameter 0.508, hole 0.254, TOP to BOTTOM, 512 vias

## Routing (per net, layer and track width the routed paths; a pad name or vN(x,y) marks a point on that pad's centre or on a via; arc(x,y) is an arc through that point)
3V3_ARD: length 34.7
  TOP w0.25: 46.76,34.11 46.92,33.95 47.11,33.95 ; R24.1 v1(97,3.6) ; 46.94,34.13 47.11,33.95 ; 47.11,33.95 U3.18 ; R23.1 v1(102.1,3.6) ; 56.95,35.45 U3.46 ; R25.1 v1(104.6,3.6)
  TOP w0.3: R31.1 65.74,30.94 v1(65.7,30.9) ; R32.1 v1(65.8,39.1) ; v1(64.69,42.39) 64.68,42.4 R26.2 ; v1(64.8,36.59) 64.79,36.6 R27.2 ; R28.2 v1(64.6,30.2)
  TOP w0.4: v1(49.85,23.75) C37.1 v1(49.1,24.55) ; v1(59,26.8) C35.1 v1(58.2,26.05) ; v1(43.3,40.6) C36.1 v1(42.5,39.85) ; v1(53.1,42.5) C38.1 v1(52.35,43.3)
  TOP w0.6: E1.2 57.15,26.8 C35.1 ; C37.1 49.85,25.6 E3.1 ; C38.1 52.35,41.55 E4.1 ; C36.1 44.25,39.85 E2.1
  L2_PWR w0.35: 54.07,0.91 P1.4 ; P1.4 55.25,2.09 ; P1.4 54.07,3.27 ; P1.4 52.9,2.09
  BOTTOM w0.25: R40.1 v1(41.55,21.09)
  BOTTOM w0.4: R44.1 42.4,31.4 v1(45.41,34.41) 46.12,34.41 v1(46.13,34.43)
  vias: v1(56.93,37.84) v1(56.93,37.33) v1(57.43,37.84) v1(57.44,37.33)
12V_ISO: length 3.5
  TOP w0.35: P1.8 64.23,3.27 ; P1.8 65.41,2.09 ; P1.8 64.23,0.91
DGND: length 37.7
  TOP w0.35: P3.4 44.93,51.53 ; P3.4 43.75,50.35 ; P3.4 46.11,50.35 ; P3.4 44.93,49.17
  L2_PWR w0.35: P3.4 46.11,50.35 ; P3.4 43.75,50.35 ; P3.4 44.93,51.53 ; P3.4 44.93,49.17
  L3_GND w0.35: 61.69,0.91 P1.7 ; P1.7 62.87,2.09 ; P1.7 60.52,2.09 ; P1.7 61.69,3.27 ; 44.93,49.17 P3.4 ; P3.4 43.75,50.35 ; P3.4 44.93,51.53 ; P3.4 46.11,50.35 ; P1.6 59.15,3.27 ; P1.6 59.15,0.91 ; P1.6 60.33,2.09 ; P1.6 57.98,2.09
  BOTTOM w0.35: 57.98,2.09 P1.6 ; P1.6 59.15,3.27 ; P1.6 59.15,0.91 ; P1.6 60.33,2.09 ; P1.7 61.69,3.27 ; P1.7 61.69,0.91 ; P1.7 60.52,2.09 ; P1.7 62.87,2.09 ; 44.93,49.17 P3.4 ; P3.4 46.11,50.35 ; P3.4 44.93,51.53 ; P3.4 43.75,50.35
  vias: v1(31.96,35.91) v1(32.71,35.91) v1(33.66,20.73) v1(34.31,36.01) v1(34.31,35.26) v1(34.31,29.01) v1(34.31,28.26) v1(34.31,27.16) v1(34.31,26.41) v1(34.56,20.66) v1(35.08,24.75) v1(35.2,28.7) v1(37,20.5) v1(37.08,44.75) v1(37.08,36.75) v1(39.08,48.75) v1(39.62,20.55) v1(39.8,32.6) v1(40.9,33) v1(41.08,36.75) v1(41.66,24.16) v1(42.21,27.69) v1(42.45,38.8) v1(42.77,25.27) v1(42.9,34.8) v1(42.9,33.99) v1(42.93,33.27) v1(43.08,48.75) v1(43.1,27.71) v1(43.3,38.1) v1(43.7,37.1) v1(43.7,36.5) v1(43.7,35.3) v1(43.84,20.57) v1(43.89,27.69) v1(43.89,24.21) v1(44.4,35.5) v1(44.75,29.64) v1(44.75,28.88) v1(45.8,40.3) v1(46.33,29.92) v1(46.33,28.93) v1(46.35,31.52) v1(46.8,40.3) v1(46.91,25.7) v1(47.08,48.75) v1(47.7,39.9) v1(48.2,20.6) v1(48.5,40.7) v1(48.59,26.52) v1(49.07,36.22) v1(49.07,31.19) v1(49.2,34.62) v1(49.2,32.79) v1(49.21,21.71) v1(49.3,27.76) v1(49.3,26.9) v1(49.5,40.7) v1(50.21,21.71) v1(50.6,42.45) v1(50.7,36.09) v1(50.7,34.62) v1(50.7,32.79) v1(50.7,31.32) v1(50.85,23.75) v1(51.08,48.75) v1(51.21,21.71) v1(51.3,43.3) v1(51.6,24.5) v1(52.2,20.6) v1(52.4,27) v1(52.53,36.09) v1(52.52,34.62) v1(52.53,32.79) v1(52.53,31.32) v1(52.5,23.65) v1(52.65,40.2) v1(52.65,39.45) v1(53.4,40.2) v1(53.4,27) v1(53.6,21.4) v1(54,34.62) v1(54,32.79) v1(54.13,36.22) v1(54.13,31.19) v1(54.35,26.7) v1(54.94,38.23) v1(55.08,48.75) v1(55.08,24.75) v1(55.85,26.75) v1(57.08,44.75) v1(57.08,20.75) v1(58.2,37.5) v1(58.8,31) v1(59,35.55) v1(59,27.8) v1(59.08,48.75) v1(59.08,40.75) v1(59.15,36.93) v1(59.08,24.75) v1(59.5,29.7) v1(59.75,27.8) v1(61.08,36.75) v1(61.08,20.75) v1(63.08,48.75) v1(63.08,40.75) v1(63.08,24.75) v1(65.08,44.75) v1(65.08,20.75) v1(67.08,48.75) v1(67.08,24.75) v1(69.08,44.75) v1(69.08,20.75) v1(71.08,48.75) v1(71.08,40.75) v1(71.1,37.2) v1(71.08,24.75) v1(71.08,8.75) v1(71.3,9.9) v1(71.3,7.4) v1(71.9,36.1) v1(72.2,11) v1(72.2,8.8) v1(72.2,6.4) v1(72.9,29.85) v1(73.08,44.75) v1(73.08,36.75) v1(73.08,20.75) v1(73.3,28.25) v1(73.3,11) v1(73.3,8.8) v1(73.3,6.4) v1(75.08,48.75) v1(75.08,40.75) v1(75.08,24.75) v1(77.08,44.75) v1(77.08,36.75) v1(77.08,20.75) v1(77.1,19.7) v1(77.1,18.5) v1(77.1,17.3) v1(78.15,23.75) v1(78.5,16.1) v1(79.08,48.75) v1(79.08,40.75) v1(79.08,32.75) v1(79.7,19.7) v1(79.7,18.5) v1(79.7,17.3) v1(81.08,44.75) v1(81.08,36.75) v1(81.08,28.75) v1(81.08,4.75) v1(82,8.7) v1(83.08,48.75) v1(83.08,40.75) v1(83.08,32.75) v1(83.08,16.75) v1(83.2,7.9) v1(83.2,6.7) v1(83.2,5.5) v1(84.5,4.2) v1(85.08,44.75) v1(85.08,36.75) v1(85.08,28.75) v1(85.8,7.9) v1(85.8,6.7) v1(85.8,5.5) v1(87.08,48.75) v1(87.08,40.75) v1(87.08,32.75) v1(87.08,24.75) v1(87.08,8.75) v1(89.08,44.75) v1(89.08,36.75) v1(89.08,28.75) v1(89.08,20.75) v1(89.08,4.75) v1(91.08,48.75) v1(91.08,40.75) v1(91.08,32.75) v1(91.08,24.75) v1(91.08,8.75) v1(92.15,7.9) v1(93.08,44.75) v1(93.08,36.75) v1(93.08,28.75) v1(93.08,20.75) v1(93.65,7.25) v1(94.7,6.75) v1(95.08,48.75) v1(95.08,40.75) v1(95.08,32.75) v1(95.08,24.75) v1(95.08,16.75) v1(97.08,44.75) v1(97.08,36.75) v1(97.08,28.75) v1(97.08,20.75) v1(97.08,12.75) v1(99.08,48.75) v1(99.08,40.75) v1(99.08,32.75) v1(99.08,24.75) v1(99.08,16.75) v1(99.95,9.5) v1(101.08,44.75) v1(101.08,36.75) v1(101.08,28.75) v1(101.08,20.75) v1(101.08,12.75) v1(101.25,8.3) v1(103.08,48.75) v1(103.08,40.75) v1(103.08,32.75) v1(103.08,24.75) v1(103.08,16.75) v1(103.08,8.75) v1(105.08,44.75) v1(105.08,36.75) v1(105.08,28.75) v1(105.08,20.75) v1(105.08,12.75) v1(107.08,48.75) v1(107.08,40.75) v1(107.08,32.75) v1(107.08,24.75) v1(107.08,16.75) v1(107.08,8.75) v1(109.08,20.75) v1(109.08,12.75) v1(109.08,4.75) v1(111.08,24.75) v1(111.08,16.75) v1(111.08,8.75)
GND:
  vias: v1(13.54,1.04) v1(13.69,9.68) v1(14.3,5.54) v1(15.11,3.12) v1(15.16,5.51) v1(15.52,50.8) v1(15.52,49.02) v1(16.05,5.51) v1(16.71,45.31) v1(16.69,43.89) v1(16.69,42.6) v1(16.74,25.25) v1(16.76,24.38) v1(16.76,23.52) v1(16.89,46.53) v1(16.89,28.7) v1(16.94,5.49) v1(17.04,32.94) v1(17.04,32.16) v1(17.27,50.8) v1(17.32,47.45) v1(17.45,9.68) v1(17.6,0.74) v1(17.81,46.56) v1(18.06,28.7) v1(18.24,36.93) v1(18.21,36.02) v1(18.36,9.65) v1(19.05,50.77) v1(19.13,28.65) v1(20.27,28.65) v1(20.27,24.89) v1(21.11,0.74) v1(21.23,24.89) v1(21.39,27.66) v1(21.36,26.54) v1(21.4,18.2) v1(21.4,17.3) v1(21.51,48.77) v1(21.46,5.36) v1(22.23,5.36) v1(22.35,27.64) v1(22.35,26.57) v1(22.66,3.71) v1(22.66,0.91) v1(23.5,4.65) v1(24.04,48.74) v1(24.43,26.74) v1(24.51,8.61) v1(24.69,20.95) v1(25.02,26.74) v1(25.5,0.74) v1(25.88,9.17) v1(25.88,8.03) v1(26.34,51.49) v1(26.34,49.48) v1(27.28,8.61) v1(27.53,0.89) v1(27.56,4.06) v1(28.12,8.56) v1(28.12,7.75) v1(28.37,15.98) v1(28.4,4.06) v1(28.45,2.21) v1(28.62,10.91) v1(28.6,10.03) v1(29.39,0.79) v1(29.46,42.7) v1(29.49,41.96) v1(29.57,40.69) v1(29.95,16.03) v1(30.91,42.7) v1(30.89,1.42) v1(31.29,16.03) v1(31.34,0.66) v1(31.62,42.7) v1(31.78,1.45) v1(32.18,0.66) v1(32.82,47.96) v1(32.82,47.29) v1(32.82,46.66) v1(32.82,46) v1(33.02,0.66) v1(33.32,16) v1(34.49,15.52) v1(35,2.95) v1(35.79,15.54) v1(35.79,2.95) v1(36.5,6.4) v1(36.58,2.95) v1(37.52,2.08) v1(37.52,1.19) v1(37.62,5.05) v1(37.59,4.29) v1(38,9.5) v1(38,6.4) v1(38.02,2.97) v1(39.32,17.88) v1(39.34,17.09) v1(39.34,16.31) v1(39.3,8.7) v1(39.3,7.1) v1(39.37,4.24) v1(39.4,0.89) v1(39.8,2.95) v1(39.98,17.5) v1(39.98,16.71) v1(40.13,5.92) v1(40.13,5.13) v1(40.13,4.27) v1(41.1,16.97) v1(41.1,15.32) v1(41.63,0.91) v1(42.14,2.95) v1(44.12,2.92) v1(44.12,0.91) v1(47.45,17.04) v1(47.45,15.44) v1(47.5,13.49) v1(47.5,12.27) v1(47.52,11.02) v1(48.36,17.73) v1(48.9,13.49) v1(48.92,12.27) v1(48.92,11.02) v1(49.07,16.64) v1(49.5,5.36) v1(49.48,4.65) v1(49.89,16.64) v1(50.37,9.5) v1(50.72,16.64) v1(51.08,9.5) v1(51.56,16.64) v1(51.79,9.5) v1(52.04,17.75) v1(52.15,5.38) v1(52.12,4.65)
GND_EARTH: length 106.1
  TOP w1.5: C22.1 7.1,26 2.01,20.9 2.01,13.41 3.52,11.9 P7.1
  TOP w1.524: P8.1 6.55,31.4 C23.1
  BOTTOM w1.5: R2.1 14.65,34.85 12.99,34.85 C6.2 7.3,33.25 P8.1 5.93,31.88 3.78,31.88 1.5,34.16 1.5,42.85 3.8,45.15 8.38,45.15 ; C5.2 6.25,11.65 P7.1 3.51,11.9 2.01,13.41 2.01,20.91 4.75,23.65 C2.2 10.61,23.65 11.91,22.35 13.56,22.35 R1.1 14.25,21.74 C3.1 14.25,27.92 15.14,28.8
  BOTTOM w1.524: R2.1 15.14,35.26 C4.1 15.14,28.8 ; C1.2 8.38,45.15
_N149: length 12.4
  TOP w0.35: P7.2 6,17.01 ; P7.2 7.3,15.71 ; P7.2 4.7,15.71 ; P7.2 6,14.41
  BOTTOM w0.5: P7.2 5.69,15.4 4.5,15.4 4.1,15.8 D1.2
  BOTTOM w1.5: C5.1 6.04,15.75 P7.2
_N150: length 12.2
  TOP w0.35: 4.7,19.52 P7.3 ; P7.3 6,18.22 ; P7.3 7.3,19.52 ; P7.3 6,20.82
  BOTTOM w0.5: P7.3 5.87,19.65 4.45,19.65 4.1,19.3 D1.1
  BOTTOM w1.5: P7.3 6.03,19.55 C2.1
_N154:
  vias: v1(40.54,10.46) v1(40.48,9.77) v1(41.43,10.44) v1(41.4,9.75)
_N157: length 5.6
  BOTTOM w0.25: U1.5 25.15,6.51 24.87,6.22 24.87,4.95 23.5,3.58 JP1.2
_N158: length 14.2
  L2_PWR w0.25: v1(26.7,3.4) 26.7,3.83 23.19,7.34 23.19,10.59 23.77,11.18 25.58,11.18 v1(25.76,11.36)
  BOTTOM w0.25: U1.10 26.15,10.85 25.76,11.24 v1(25.76,11.36) ; v1(26.7,3.4) 26.7,2.21 JP2.2
_N217: length 13.6
  TOP w0.35: 4.7,35.76 P8.2 ; P8.2 6,34.45 ; P8.2 7.3,35.76 ; P8.2 6,37.06
  BOTTOM w0.5: D2.2 4.52,35.76 P8.2
  BOTTOM w1.5: C6.1 7.59,37.35 P8.2
_N218: length 13.6
  TOP w0.35: P8.3 7.3,39.57 ; P8.3 6,40.87 ; P8.3 6,38.26 ; P8.3 4.7,39.57
  BOTTOM w0.5: P8.3 4.46,39.57 D2.1
  BOTTOM w1.5: P8.3 7.48,41.05 C1.1
_N234: length 9
  TOP w0.25: v1(26.29,6.15) 26.19,6.15 26.14,6.1 v1(23.4,6.1)
  BOTTOM w0.25: v1(23.4,6.1) 23.4,6.2 23.5,6.3 23.5,6.4 23.8,6.7 23.8,9.93 23.09,10.63 ; v1(26.29,6.15) 26.15,6.29 U1.3
_N460: length 25
  TOP w0.25: v1(60.07,44.31) 61.78,44.31 P9.1 ; v1(46.5,32.26) 46.69,32.45 U3.21
  BOTTOM w0.25: v1(46.5,32.26) 46.81,32.58 46.81,37.74 47.9,38.84 54.6,38.84 v1(60.07,44.31)
_N461: length 1.9
  TOP w0.6: R26.1 62.6,44.29 P9.2
_N467: length 1.9
  TOP w0.6: R27.1 62.6,38.49 P10.2
_N473: length 1.9
  TOP w0.6: R28.1 62.6,32.09 P11.2
_N477: length 8.1
  TOP w0.25: P10.1 56.5,38.5 55.95,37.95 55.95,37.04 55.36,36.45 U3.48
_N478: length 7
  TOP w0.25: U3.41 55.7,32.95 56.05,32.6 56.5,32.6 57,32.1 P11.1
_N491:
  vias: v1(31.4,26.5) v1(31.4,25.9) v1(31.4,20.8) v1(31.4,20.2) v1(32.1,26.5) v1(32.1,25.9) v1(32.1,20.8) v1(32.1,20.2)
_N516:
  vias: v1(31.4,34.7) v1(31.4,34.1) v1(31.4,28.9) v1(31.4,28.3) v1(32.1,34.7) v1(32.1,34.1) v1(32.1,28.9) v1(32.1,28.3)
_N712:
  vias: v1(55.5,11.3) v1(56.3,11.3) v1(57.1,11.3)
_N767: length 4
  BOTTOM w0.381: R43.2 27.22,27.93 28.04,28.75 28.04,29.84
  BOTTOM w0.4: Q9.4 28.57,30.37 28.04,29.84
CEXT_2: length 2.1
  TOP w0.25: C47.2 49.5,38.85 50.35,38 U3.9
CEXT_3: length 2.4
  TOP w0.25: C56.1 48.5,38.8 49.04,38.26 49.27,38.26 49.85,37.68 U3.10
CEXT_6: length 1.4
  TOP w0.25: C52.1 52.4,29.67 52.35,29.72 U3.32
CEXT_7: length 1.6
  TOP w0.25: C57.1 53.4,29.17 52.85,29.72 U3.33
CLK_REF: length 14.4
  TOP w0.25: v1(54,38.24) 54.35,37.89 U3.1 ; U3.22 47.18,31.95 v1(47.05,31.81)
  BOTTOM w0.25: v1(47.05,31.81) 47.9,32.67 47.9,36.9 48.72,37.72 53.48,37.72 v1(54,38.24)
INT_N: length 69.1
  TOP w0.25: v1(105.6,5.7) R25.2 105.6,2.13 P5.6 ; v1(56.21,32.02) 56.14,31.95 U3.39
  BOTTOM w0.25: v1(105.6,5.7) 104.55,6.75 100.85,6.75 72.7,34.9 56.65,34.9 55.9,34.15 55.9,32.82 56.21,32.51 v1(56.21,32.02)
LGATE1: length 8.8
  BOTTOM w0.25: U1.9 25.65,10.62 25.1,11.17 25.1,11.8 25.27,11.97 27.53,11.97 28,11.5 28,11.1 27.8,10.9 27.8,9.78 28.38,9.2 29.39,9.2 29.42,9.16
LGATE2: length 7.5
  BOTTOM w0.25: U1.8 25.15,10.48 24.6,11.03 24.6,12 25.02,12.42 27.98,12.42 28.7,11.7 29.42,11.7 Q3.4
LT4256_GATE:
  vias: v1(24.88,48.54) v1(25.58,48.53) v1(32.63,52.02) v1(32.62,51.32)
LT4256_OUT: length 0
  BOTTOM w0.381: 24.42,31.43 R39.1
  vias: v1(10.25,51.26) v1(10.25,50.51) v1(10.25,49.61) v1(10.25,48.86) v1(25.26,31.94) v1(27.81,51.46) v1(27.81,50.71) v1(28.66,51.46) v1(28.66,50.71) v1(32.82,40.01) v1(32.82,39.34) v1(32.82,38.71) v1(32.82,38.05)
LT4256_PWRGD: length 13.8
  L2_PWR w0.381: v1(23.48,28.99) 23.48,28.67 23.1,28.28 21.55,28.28 20.2,29.63 20.2,35.6 21.29,36.69 v1(21.46,36.69)
  BOTTOM w0.381: C65.1 21.22,36.93 v1(21.46,36.69)
LT4256_UV_ISO: length 82.3
  TOP w0.25: v1(94.4,7.6) 105.21,7.6 P5.8
  BOTTOM w0.25: R41.1 40.7,26.4 44.15,22.95 79.05,22.95 v1(94.4,7.6)
LT8304_EN: length 42.6
  TOP w0.25: v1(24.08,5.26) 25.35,3.99 25.35,3.43 25.96,2.82 28.98,2.82 29.76,3.6 45.07,3.6 49.56,8.09 49.56,14.26 50.9,15.6 v1(52,15.6)
  BOTTOM w0.25: v1(52,15.6) 52,14.88 51.33,14.21 U2.1 ; v1(24.08,5.26) 24.08,6.11 24.65,6.68 U1.6
LTC_GATE: length 7.6
  TOP w0.25: v1(23.92,11.76) 24.36,11.76 24.56,11.96 27.04,11.96 27.35,11.65 v1(27.35,11.3)
  BOTTOM w0.25: U1.12 27.15,10.55 27.35,10.75 v1(27.35,11.3) ; 24.9,13.22 Q4.4 24.37,13.25 23.92,12.8
  BOTTOM w0.35: v1(23.92,11.76) 23.92,12.8
LTC_OUT: length 13
  L2_PWR w0.25: v1(26.6,11.3) 26.6,10.97 30.37,7.2 36.46,7.2
  BOTTOM w0.25: U1.11 26.65,11.15 26.6,11.2 v1(26.6,11.3)
  vias: v1(27.06,44.79) v1(27.68,44.93) v1(28.23,34.86) v1(28.94,34.86) v1(37.07,14.05) v1(37.07,13.35) v1(37.67,14.05) v1(37.67,13.35) v1(38.27,14.05) v1(38.27,13.35) v1(43,6.4) v1(43,5.8) v1(43,5.2) v1(43.9,4.2) v1(44.6,4.2) v1(52.48,11.73) v1(52.5,10.97) v1(53.24,10.31) v1(54.15,10.31)
P1_LED_0/SPI_CFG1: length 41.4
  TOP w0.25: v1(44.22,25.88) 42.49,25.88 40.69,27.69 40.69,31.57 41.81,32.69 45.37,32.69 46.12,33.45 48.1,33.45 U3.19 ; v1(65.7,27.1) JP3.2
  BOTTOM w0.25: v1(44.22,25.88) 45.49,25.88 48.01,28.4 62.2,28.4 63.5,27.1 v1(65.7,27.1)
P1_TXN: length 21.4
  TOP w0.17: D10.1 34.09,24.3 34.39,24 34.39,23.66 34.56,23.49 45.75,23.49 47.61,25.35 47.61,27.41 49.16,28.97 49.55,28.97 49.96,29.38 49.96,29.67 49.91,29.72 49.91,30.14 U3.27
P1_TXP: length 21.9
  TOP w0.17: U3.28 50.29,30.14 50.29,29.72 50.26,29.68 50.26,29.25 49.68,28.67 49.28,28.67 47.9,27.29 47.9,25.22 45.87,23.19 34.55,23.19 34.38,23.02 34.38,22.7 34.04,22.36 D9.1
P2_LED_0/P2_SWPD_EN_N: length 13.1
  TOP w0.25: v1(56.24,36.2) 55.99,35.95 U3.47
  TOP w0.3: v1(59.87,35.95) 60.52,35.3 JP4.2
  BOTTOM w0.25: v1(59.87,35.95) 59.62,36.2 v1(56.24,36.2)
P2_TXN: length 41.8
  TOP w0.17: U3.4 52.85,37.72 52.77,37.8 52.77,38.11 55.01,40.35 55.01,43.71 53.79,44.93 39.33,44.93 38.5,44.1 38.5,32.85 37.85,32.2 34.48,32.2 34.31,32.37 34.31,32.73 34.14,32.9 D12.1
P2_TXP: length 42
  TOP w0.17: U3.5 52.35,37.74 52.47,37.86 52.47,38.24 54.71,40.48 54.71,43.59 53.66,44.64 39.45,44.64 38.8,43.98 38.8,32.73 37.97,31.9 36.37,31.9 arc(36.15,31.81) 36.05,31.58 arc(35.96,31.36) 35.74,31.27 35.69,31.27 arc(35.47,31.36) 35.37,31.58 arc(35.28,31.81) 35.06,31.9 34.48,31.9 34.31,31.73 34.31,31.37 34.14,31.2 D11.1
POWER_AND_DATA_N1:
  vias: v1(16.4,17) v1(16.4,16.05) v1(16.9,22.2) v1(16.9,21.25)
POWER_AND_DATA_P2:
  vias: v1(16.35,41.25) v1(16.35,40.3) v1(17.15,35.05) v1(17.15,34.1)
POWER_N: length 22.9
  BOTTOM w0.25: Q3.5 36.25,11.71 37,10.96 37,7.9 36.1,7 32.67,7 31.79,6.12 31.79,3.05 31.04,2.3 Q2.3 30.76,2.49 30.76,3.86 28.55,6.07 27.33,6.07 26.65,6.75 U1.2
  vias: v1(13.3,11.4) v1(13.3,10.6) v1(14,11.4) v1(14,10.6) v1(31.2,11.6) v1(31.2,10.5) v1(31.9,11.6) v1(31.9,10.5)
POWER_P: length 11.2
  BOTTOM w0.25: 34.96,9.16 33.28,9.16 32.12,8.01 32.12,7.28 30.95,6.11 Q1.3 30.03,5.3 28.7,6.63 27.47,6.63 27.15,6.95 U1.1
  vias: v1(13.3,19.1) v1(13.3,18.3) v1(14,19.1) v1(14,18.3) v1(31.2,9.1) v1(31.2,8) v1(31.9,9.1) v1(31.9,8)
PWRGD_ISO: length 64.5
  BOTTOM w0.25: P5.1 92.94,8.16 78.69,22.41 44.12,22.41 43.82,22.1 40.5,22.1
RESET_N: length 91.9
  TOP w0.25: v1(94.35,8.6) v1(99.95,8.6) ; U3.20 46.34,32.95 45.62,32.23 42.19,32.23 41.22,31.27 41.22,27.84 42.57,26.49 v1(44.73,26.49)
  BOTTOM w0.25: v1(99.95,8.6) 101.1,7.45 105,7.45 106.85,5.6 106.85,3.42 P5.7 ; v1(44.73,26.49) 45.39,26.49 47.85,28.96 73.99,28.96 v1(94.35,8.6)
SCCP: length 21.7
  L2_PWR w0.25: 34.14,4.27 v1(34.14,2.9) ; 34.14,4.27 33.94,4.47 ; 34.14,4.27 34.14,4.67 ; 34.14,4.67 v1(34.14,5.96) ; 34.14,4.67 33.94,4.47 ; 33.94,4.47 29.31,4.47 29.11,4.67 26.67,4.67 23.7,7.65 23.7,10.19 v1(24.1,10.59)
  BOTTOM w0.25: v1(34.14,5.96) 32.88,5.96 Q1.1 ; U1.7 24.65,10.2 24.25,10.59 v1(24.1,10.59) ; v1(34.14,2.9) 32.89,2.9 32.85,2.94
SPI_CS: length 64
  TOP w0.25: U3.45 58.45,34.95 v1(59.1,34.3) ; P5.5 103.1,2.09 R23.2 v1(103.1,6.11)
  BOTTOM w0.25: v1(103.1,6.11) 100.55,6.11 72.35,34.3 v1(59.1,34.3)
SPI_MISO: length 59.4
  TOP w0.25: U3.43 56.32,33.95 56.44,33.83 v1(56.54,33.83) ; P5.3 98,2.11 R24.2 v1(98,5.4)
  BOTTOM w0.25: v1(56.54,33.83) 57.12,34.4 58.1,34.4 59.6,32.9 71.95,32.9 98,6.85 v1(98,5.4)
SPI_MOSI: length 60.6
  TOP w0.25: v1(59.8,33.6) 59.35,33.15 56.32,33.15 56.02,33.45 U3.42
  BOTTOM w0.25: P5.4 100.56,5.19 72.15,33.6 v1(59.8,33.6)
SPI_SCK: length 57.5
  TOP w0.25: v1(57.73,33.78) 57.06,34.45 U3.44
  BOTTOM w0.25: v1(57.73,33.78) 59.21,32.3 71.6,32.3 95.48,8.42 P5.2
XTAL_I: length 6.5
  TOP w0.25: Y1.1 42.71,30.81 42.96,31.06 45.43,31.06 C55.1 45.74,30.76 46.86,30.76 47.55,31.45 U3.23
XTAL_O: length 6.6
  TOP w0.25: Y1.3 44.62,28 C58.1 46.34,28 47.02,28.68 47.02,30.1 47.86,30.95 U3.24

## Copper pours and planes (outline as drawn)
3V3_ARD on TOP: 44.36,34.83 44.36,33.1 45.15,33.1 45.15,33.93 47.04,33.93 47.04,34.83
3V3_ARD on TOP: 56.68,38.13 56.68,36.08 56,35.4 56.63,35.4 56.68,35.35 56.68,35.31 57.66,35.31 57.66,38.13
3V3_ARD on L2_PWR: 56.52,52.6 109.1,52.6 109.1,26.1 113.7,26.1 113.7,0.4 52.7,0.4 52.7,2.67 53.63,3.6 70.5,3.6 70.5,20.22 41.05,20.22 41.05,21.67 41.4,22.02 46.74,22.02 48.49,23.77 48.49,25.68 50.55,27.74 50.55,29.69 48.03,29.69 47.73,30 47.73,31.19 45.11,33.81 45.11,36.83 42.06,39.88 42.06,40.61 43.38,41.94 50.62,41.94 52.37,43.69 52.78,43.69 53.64,42.82 53.64,42.01 51.87,40.23 51.87,37.67 53.64,37.67 56.52,40.54 ; 1 cut-out
12V_ISO on TOP: 62.9,5.5 62.9,0.4 67.1,0.4 67.1,3.7 76.3,3.7 76.3,7.2 74.4,7.2 74.4,5.5
DGND on TOP: 35.81,52.6 109.1,52.6 109.1,26.1 113.7,26.1 113.7,0.5 70.5,0.5 70.5,20.22 35.27,20.22 33.46,18.4 30.83,18.4 30.83,19.58 32.7,19.58 32.7,21.4 34.18,21.4 34.18,25.27 32.7,25.27 32.7,29.3 34.18,29.3 34.18,33.76 32.7,33.76 32.7,35.5 30.9,35.5 30.9,36.41 35.81,36.41 ; 1 cut-out
DGND on BOTTOM: 35.81,52.6 109.1,52.6 109.1,26.1 113.7,26.1 113.7,0.4 52.7,0.4 52.7,2.64 53.66,3.6 70.5,3.6 70.5,20.22 33.1,20.22 33.1,35.5 31.66,35.5 31.66,36.41 35.81,36.41
DGND on L2_PWR: 35.81,52.6 56.03,52.6 56.03,40.61 53.34,37.92 52.12,37.92 52.12,39.95 53.95,41.78 53.95,43.08 53.09,43.94 52.22,43.94 50.5,42.21 43.26,42.21 41.78,40.74 41.78,39.75 44.68,36.86 44.68,33.5 46.25,31.93 42.04,31.93 41.61,31.5 41.61,27.66 42.01,27.25 46.1,27.25 48.16,29.31 50.16,29.31 50.16,27.76 48.11,25.7 48.11,23.98 46.56,22.43 41.15,22.43 40.67,21.95 40.67,20.24 40.69,20.22 31.11,20.22 31.11,36.4 35.81,36.4
DGND on L3_GND: 35.81,52.6 109.1,52.6 109.1,26.1 113.7,26.1 113.7,0.4 55.17,0.4 55.17,3.6 70.5,3.6 70.5,20.22 35.27,20.22 34.89,19.84 31.65,19.84 31.65,36.26 35.81,36.26
GND on TOP: 14.7,52.41 14.7,47.91 14.55,47.76 3.75,47.76 3.75,43.61 9.6,43.61 9.6,44.71 10.85,45.96 18.4,45.96 20.06,47.61 20.06,52.36 20,52.41
GND on TOP: 30.58,48.24 30.58,45.41 33.21,45.41 33.21,48.24
GND on TOP: 32.9,0.4 44.5,0.4 44.5,3.9 51.75,3.9 52.75,4.9 52.75,9.45 52.22,9.45 52.22,9.85 49.19,9.85 49.19,14.44 50.85,16.1 52.51,16.1 52.51,18.31 35.79,18.31 34.42,16.94 32.9,16.94
GND on BOTTOM: 30.06,17.6 34.26,17.6 34.92,18.26 54.69,18.26 54.69,7.43 54.05,6.79 52.98,6.79 52.76,6.57 52.76,4.88 52.23,4.36 44.5,4.36 44.5,0.41 12.9,0.41 12.9,10 14.7,10 14.7,13 18.1,13 18.1,15 18.2,15 18.2,19.7 16.2,19.7 16.2,25.3 16.53,25.63 16.53,32.95 17.68,34.09 17.68,36.8 16.2,38.28 16.2,52.6 26.61,52.6 26.61,43.36 32.16,43.36 32.16,39.56 30.06,39.56
GND on L3_GND: 12.9,19.5 12.9,0.41 44.5,0.41 44.5,3.9 51.75,3.9 53.21,5.36 58.3,5.36 58.3,18.16 36.98,18.16 35.31,16.48 27.1,16.48 27.1,19.89 25.12,19.89 25.12,32.33 27.13,32.33 27.13,37.6 29.41,37.6 33.21,41.4 33.21,52.58 13.6,52.58 13.6,48.1 16.2,48.1 16.2,19.5
_N149 on TOP: 4.05,17.3 4.05,14.2 11.6,14.2 11.6,11.9 13.1,11.9 13.1,17.3
_N150 on TOP: 4.05,21.2 4.05,17.55 13.1,17.55 13.1,23.5 11.6,23.5 11.6,21.2
_N151 on BOTTOM: 16,17.6 16,15 14.8,15 14.8,17.6
_N152 on BOTTOM: 20.8,10 20.8,8.4 20.3,8.4 20.3,5.7 18.2,5.7 18.2,8.4 19,8.4 19,10
_N153 on BOTTOM: 23.5,16.7 23.5,14 22.6,14 22.6,15 21.7,15 21.7,16.7
_N154 on TOP: 40.17,10.8 40.17,6.7 46.7,6.7 46.7,18.3 41.7,18.3 41.7,10.8
_N154 on BOTTOM: 41.8,7.64 41.8,10.81 40.17,10.81 40.17,7.64
_N155 on BOTTOM: 35.2,5.5 35.2,3.9 33.6,3.9 33.6,4.2 32.3,4.2 32.3,5.1 33.6,5.1 33.6,5.5
_N156 on BOTTOM: 35.2,2.4 35.2,0.8 33.6,0.8 33.6,1.2 32.3,1.2 32.3,2.1 33.6,2.1 33.6,2.4
_N217 on TOP: 4.05,37.46 4.05,34.16 11.6,34.16 11.6,33.65 13.1,33.65 13.1,38.86 9.35,38.86 7.95,37.46
_N218 on TOP: 11.6,45.16 11.6,41.81 4.25,41.81 4.25,38.01 7.26,38.01 8.85,39.6 13.1,39.6 13.1,45.16
_N234 on BOTTOM (solid shape): 27.18,14.22 24.62,14.22 24.62,16.98 27.18,16.98
_N234 on BOTTOM: 15.3,11.8 15.3,10.3 23.32,10.3 23.32,11.8 20.7,11.8 20.7,18.8 24.3,18.8 24.3,14.1 27.5,14.1 27.5,20.2 19.1,20.2 19.1,11.8
_N431 on TOP: 66.9,26.54 66.9,25.89 69.56,25.89 69.56,26.71 68.7,26.71 68.7,26.54
_N432 on TOP: 66.9,28.4 66.9,27.66 68.7,27.66 68.7,27.5 69.43,27.5 69.43,27.36 70.18,27.36 70.18,28.56 69.43,28.56 69.43,28.4
_N433 on TOP: 67.71,31.2 67.71,30.45 70.17,30.45 70.17,29.6 70.83,29.6 70.83,31.2
_N434 on TOP: 66.38,32.34 66.38,31.51 67.42,31.51 67.42,31.45 68.48,31.45 68.48,32.34
_N448 on TOP: 66.9,34.74 66.9,34.09 69.56,34.09 69.56,34.91 68.7,34.91 68.7,34.74
_N449 on TOP: 66.9,36.6 66.9,35.86 68.7,35.86 68.7,35.7 69.43,35.7 69.43,35.56 70.18,35.56 70.18,36.76 69.43,36.76 69.43,36.6
_N450 on TOP: 67.71,39.34 67.71,38.55 70.17,38.55 70.17,37.82 70.83,37.82 70.83,39.34
_N451 on TOP: 66.3,40.5 66.3,39.67 67.34,39.67 67.34,39.6 68.4,39.6 68.4,40.5
_N489 on TOP: 12.8,27.95 12.8,24.05 15.55,24.05 15.55,25.85 18.7,25.85 18.7,27.95
_N490 on TOP: 19.43,27.69 19.43,25.86 19.84,25.45 24.71,25.45 24.97,25.2 24.97,22.94 23.5,21.46 23.5,19.96 23.93,19.96 23.93,21.34 25.35,22.76 25.35,25.37 24.84,25.88 21.21,25.88 20.75,26.34 20.75,27.69
_N491 on TOP: 29.3,21.2 29.3,18.3 30.57,18.3 30.57,19.9 32.4,19.9 32.4,21.2
_N491 on TOP: 32.4,25.5 32.4,27.11 29.46,27.11 28.41,26.06 26.92,26.06 26.04,25.17 26.04,23.9 26.7,23.9 26.7,25.15 27.05,25.5
_N491 on BOTTOM: 31.1,19.9 31.1,26.9 32.4,26.9 32.4,19.9
_N514 on TOP: 12.8,33.3 12.8,29.45 18.7,29.45 18.7,31.5 15.55,31.5 15.55,33.3
_N515 on TOP: 20.47,31.09 23.93,27.64 23.93,26.47 23.47,26.47 23.47,27.46 21.08,29.84 19.43,29.84 19.43,31.29 20.47,31.29
_N516 on TOP: 29.46,28 32.4,28 32.4,29.2 29.46,29.2
_N516 on TOP: 29.7,36.5 29.7,35.2 29.49,35.2 29.49,34.53 27.97,33 27.97,32.66 26.97,31.67 26.09,31.67 26.09,30.43 26.61,30.43 26.61,30.81 28.27,32.49 28.27,32.84 29.23,33.8 32.4,33.8 32.4,35 30.59,35 30.59,36.5
_N516 on BOTTOM: 31.1,28 31.1,35 32.4,35 32.4,28
_N676 on TOP: 50.75,38.2 50.75,37.93 51.1,37.93 51.26,37.77 51.26,36.75 51.94,36.75 51.94,38.01 51.3,38.65 51.3,40.5 51.7,40.9 51.7,41.85 50.3,41.85 50.3,38.65
_N682 on TOP: 50.65,25.15 51.85,25.15 51.85,26.37 51.57,26.65 51.57,29.38 51.45,29.5 51.45,30.65 50.75,30.65 50.75,29.5 50.65,29.4
_N687 on TOP: 43.95,37.99 46.95,37.99 47.2,37.74 47.2,36.35 48.55,36.35 48.55,36.75 48.95,36.75 48.95,37.85 48.45,38.35 48.15,38.35 47.9,38.6 47.9,38.88 45.35,38.88 45.13,39.1 43.95,39.1
_N694 on TOP: 57.6,28.95 55.76,28.95 54.61,30.1 54.61,30.65 53.75,30.65 53.75,29.45 54.21,28.99 54.21,28.05 56.1,28.05 56.5,27.65 57.6,27.65
_N709 on BOTTOM: 49.99,8.98 49.99,7.49 54.04,7.49 54.04,9.31 52.31,9.31 52.31,8.98
_N710 on BOTTOM: 45.5,9.27 45.5,4.36 46.84,4.36 46.84,9.27
_N711 on BOTTOM: 42.7,12.32 42.7,11.23 46.74,11.23 46.74,12.2 44.4,12.2 44.4,12.32
_N712 on TOP: 54.9,13.4 54.9,10.8 57.65,10.8 57.65,13.4
_N712 on BOTTOM: 47.2,9.6 47.2,4.36 48.8,4.36 48.8,5.87 57.6,5.87 57.6,13.4 54.9,13.4 54.9,7.24 48.8,7.24 48.8,10.34 46.74,10.34 46.74,10.9 42.7,10.9 42.7,9.6
_N713 on BOTTOM: 49.66,13.36 49.66,12.51 53.07,12.51 53.07,13.36
_N716 on BOTTOM: 42.12,13.47 42.12,12.6 44.7,12.6 44.7,12.5 46.73,12.5 46.73,13.47
_N721 on TOP: 77.1,15.34 77.1,4.95 80.13,4.95 80.13,9.97 85.68,9.97 85.68,15.34
_N735 on TOP: 70.5,18.3 70.5,13.8 74.3,13.8 74.3,8.1 76.5,8.1 76.5,18.3
_N738 on BOTTOM: 23.62,42.85 23.62,40.7 22.52,40.7 22.52,41.36 20.66,41.36 20.66,42.85
_N744 on BOTTOM: 24.84,43.68 24.84,39.28 20.64,39.28 20.64,40.45 23.88,40.45 23.87,43.97 24.11,44.61 24.27,45.01 25.78,45.01 25.78,43.68
_N749 on BOTTOM: 26,37.74 26,33.74 23.67,33.74 23.67,32.28 22.59,32.28 22.59,33.58 22.6,33.58 22.6,35.08 25.2,35.08 25.2,37.74
_N756 on BOTTOM: 30.2,23.5 30.2,21.1 27.9,21.1 27.9,22.5 25.8,22.5 25.8,22.3 21.9,22.3 21.9,24.3 25.8,24.3 25.8,24 27.9,24 27.9,23.5
_N810 on BOTTOM: 20.21,40.7 20.21,39.18 17.25,39.18 17.25,40.7
_N811 on BOTTOM: 41.4,31.1 41.4,29.5 39.8,29.5 39.8,29.3 37.8,29.3 37.8,31.4 39.8,31.4 39.8,31.1
_N814 on BOTTOM: 28.79,44.39 28.79,41.94 28.03,41.94 28.03,40.71 26.49,40.71 26.49,42.68 27.94,42.68 27.94,44.39
DATA_N1 on TOP: 23.9,25.15 23.9,23.93 22.91,22.94 18.08,22.94 18.08,24.21 23.34,24.21 23.5,24.36 23.5,25.15
DATA_N2 on TOP: 23.15,33.99 23.15,32.53 23.5,32.53 23.5,30.45 23.9,30.45 23.9,32.59 26.87,32.59 26.87,33.99
DATA_P1 on TOP: 26.52,18.85 26.52,17.68 23.09,17.68 22.3,18.47 22.3,21.97 23.14,22.81 23.5,22.81 24.16,23.47 24.16,25.17 24.56,25.17 24.56,23.32 23.67,22.43 23.39,22.43 22.78,21.82 22.78,19.28 23.22,18.85
DATA_P2 on TOP: 18.07,33.46 18.07,31.8 21.03,31.8 21.39,31.45 21.39,31.04 22.66,29.77 24.26,29.77 24.54,30.05 24.54,31.65 24.16,31.65 24.16,30.25 24.03,30.12 22.99,30.12 21.91,31.21 21.91,32.28 21.9,32.28 21.9,33.46
DLDO1_1P1 on TOP: 56.3,30.81 56.3,29.2 57.34,29.2 57.34,31.51 54.65,31.51 54.65,30.81
DLDO2_1P1 on TOP: 45.76,37.41 45.76,35.14 47.45,35.14 47.45,35.36 48.55,35.36 48.55,36.04 46.94,36.04 46.94,37.41
LT4256_GATE on TOP: 32.95,52.3 32.95,48.49 26.05,48.49 26.05,48.26 24.59,48.26 24.59,48.84 32.3,48.84 32.3,52.3
LT4256_GATE on BOTTOM: 25.95,45.59 24.56,45.59 24.56,48.8 25.95,48.8
LT4256_GATE on BOTTOM: 32.95,52.3 32.95,51.03 31.79,51.03 31.79,52.3
LT4256_OUT on TOP: 30.63,40.39 30.63,37.61 33.12,37.61 33.12,40.39
LT4256_OUT on TOP: 3.75,52.41 3.75,48.26 14.05,48.26 14.05,52.41
LT4256_OUT on BOTTOM: 31.42,52.6 31.42,51.03 29.03,51.03 29.03,46.82 26.97,46.82 26.97,52.6
LT4256_OUT on BOTTOM: 25.56,33.49 25.56,30.87 23.92,30.87 23.92,33.49
LT4256_OUT on L2_PWR: 9.27,48.1 9.27,52.58 33.21,52.58 33.21,37.5 29.9,37.5 29.9,38.53 28.7,39.73 28.7,48.1 28.18,48.1 26.55,46.81 25.69,46.05 25.69,31.56 24.88,31.56 24.88,48.1
LT4256_PWRGD on BOTTOM: 24.9,39.01 24.9,35.33 23.8,35.33 23.8,37.71 20.5,37.71 20.5,39.01
LT4256_PWRGD on BOTTOM: 27.8,25.6 27.8,24.3 26.1,24.3 26.1,24.6 22.92,24.6 22.92,30.36 22.06,30.36 22.06,32.01 23.66,32.01 23.66,30.53 23.75,30.53 23.75,25.6
